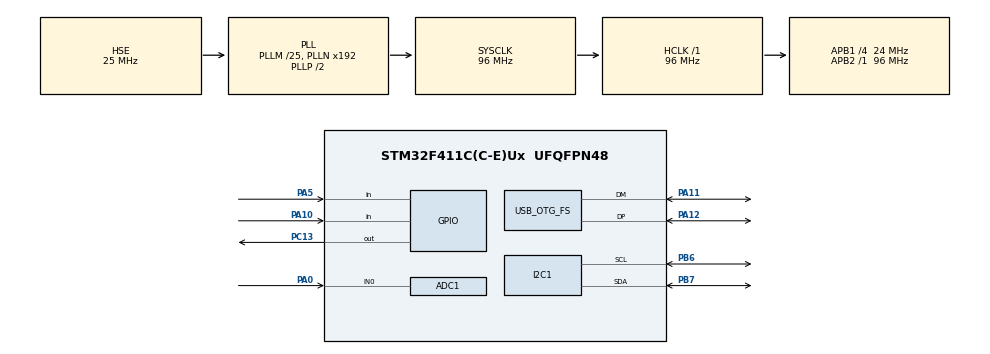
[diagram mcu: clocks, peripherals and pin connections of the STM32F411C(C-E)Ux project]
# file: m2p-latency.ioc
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ADC1.Channel-0\#ChannelRegularConversion=ADC_CHANNEL_0
ADC1.NbrOfConversionFlag=1
ADC1.Rank-0\#ChannelRegularConversion=1
ADC1.SamplingTime-0\#ChannelRegularConversion=ADC_SAMPLETIME_3CYCLES
ADC1.master=1
I2C1.I2C_Mode=I2C_Fast
Mcu.Family=STM32F4
Mcu.Name=STM32F411C(C-E)Ux
Mcu.Package=UFQFPN48
NVIC.OTG_FS_IRQn=true\:0\:0\:false\:false\:true\:true\:true\:true
NVIC.PriorityGroup=NVIC_PRIORITYGROUP_4
PA0-WKUP.Signal=ADCx_IN0
PA10.GPIO_PuPd=GPIO_PULLUP
PA10.Signal=GPIO_Input
PA11.Mode=Device_Only
PA11.Signal=USB_OTG_FS_DM
PA12.Mode=Device_Only
PA12.Signal=USB_OTG_FS_DP
PA13.Mode=Serial_Wire
PA13.Signal=SYS_JTMS-SWDIO
PA14.Mode=Serial_Wire
PA14.Signal=SYS_JTCK-SWCLK
PA5.Signal=GPIO_Input
PB6.Mode=I2C
PB6.Signal=I2C1_SCL
PB7.Mode=I2C
PB7.Signal=I2C1_SDA
PC13-ANTI_TAMP.Signal=GPIO_Output
PH0\ -\ OSC_IN.Mode=HSE-External-Oscillator
PH0\ -\ OSC_IN.Signal=RCC_OSC_IN
PH1\ -\ OSC_OUT.Mode=HSE-External-Oscillator
PH1\ -\ OSC_OUT.Signal=RCC_OSC_OUT
ProjectManager.HeapSize=0x200
ProjectManager.StackSize=0x400
ProjectManager.TargetToolchain=Makefile
RCC.48MHZClocksFreq_Value=48000000
RCC.AHBFreq_Value=96000000
RCC.APB1CLKDivider=RCC_HCLK_DIV4
RCC.APB1Freq_Value=24000000
RCC.APB1TimFreq_Value=48000000
RCC.APB2Freq_Value=96000000
RCC.APB2TimFreq_Value=96000000
RCC.CortexFreq_Value=96000000
RCC.HCLKFreq_Value=96000000
RCC.HSE_VALUE=25000000
RCC.HSI_VALUE=16000000
RCC.LSE_VALUE=32768
RCC.PLLM=25
RCC.PLLSourceVirtual=RCC_PLLSOURCE_HSE
RCC.SYSCLKFreq_VALUE=96000000
RCC.SYSCLKSource=RCC_SYSCLKSOURCE_PLLCLK
RCC.VCOOutputFreq_Value=192000000
SH.ADCx_IN0.0=ADC1_IN0,IN0
TIM2.Prescaler=47
USB_DEVICE.CLASS_NAME_FS=HID
USB_DEVICE.HID_FS_BINTERVAL=0x1
USB_DEVICE.VirtualMode=Hid
USB_DEVICE.VirtualModeFS=Hid_FS
USB_OTG_FS.VirtualMode=Device_Only
VP_TIM2_VS_ClockSourceINT.Mode=Internal
VP_USB_DEVICE_VS_USB_DEVICE_HID_FS.Mode=HID_FS
board=custom

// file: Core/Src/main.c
/* USER CODE BEGIN Header */
/**
  ******************************************************************************
  * @file           : main.c
  * @brief          : Main program body
  ******************************************************************************
  * @attention
  *
  * Copyright (c) 2026 STMicroelectronics.
  * All rights reserved.
  *
  * This software is licensed under terms that can be found in the LICENSE file
  * in the root directory of this software component.
  * If no LICENSE file comes with this software, it is provided AS-IS.
  *
  ******************************************************************************
  */
/* USER CODE END Header */
#include "main.h"
#include "usb_device.h"

/* USER CODE BEGIN Includes */

#include "ssd1306.h"
#include "display.h"
#include "measure.h"
#include "usbd_hid.h"

/* USER CODE END Includes */

ADC_HandleTypeDef hadc1;

I2C_HandleTypeDef hi2c1;

TIM_HandleTypeDef htim2;

/* USER CODE BEGIN PV */

uint32_t latencies_us[NUM_CYCLES] = {};
uint16_t cycle_index = 0;
uint8_t hid_report[HID_REPORT_SIZE] = {0};

enum MouseMode {
  CLICK = 0,
  MOVE = 1
};

enum MouseMode selectedMode = CLICK;

extern USBD_HandleTypeDef hUsbDeviceFS;

/* USER CODE END PV */

void SystemClock_Config(void);
static void MX_GPIO_Init(void);
static void MX_ADC1_Init(void);
static void MX_I2C1_Init(void);
static void MX_TIM2_Init(void);
/* USER CODE BEGIN PFP */

uint32_t clickMouse();
void releaseMouse();
uint32_t moveMouse();
void moveBackMouse();
uint8_t HID_IsIdle (const USBD_HandleTypeDef *pdev);

/* USER CODE END PFP */

/* USER CODE BEGIN 0 */

uint32_t startMouseAction() {
  if (selectedMode == CLICK) {
    return clickMouse();
  }

  return moveMouse();
}

void stopMouseAction() {
  if (selectedMode == CLICK) {
    releaseMouse();
  } else {
    moveBackMouse();
  }
}

uint32_t moveMouse() {
  HAL_TIM_Base_Stop_IT(&htim2);
  __HAL_TIM_SET_COUNTER(&htim2, 0);
  HAL_TIM_Base_Start_IT(&htim2);

  hid_report[0] = 0;
  hid_report[1] = 127;
  hid_report[2] = 127;
  while (!HID_IsIdle(&hUsbDeviceFS)) {}
  const uint32_t timestamp = __HAL_TIM_GET_COUNTER(&htim2);
  USBD_HID_SendReport(&hUsbDeviceFS, hid_report, HID_REPORT_SIZE);

  return timestamp;
}

void moveBackMouse() {
  hid_report[0] = 0;
  hid_report[1] = -127;
  hid_report[2] = -127;
  while (!HID_IsIdle(&hUsbDeviceFS)) {}
  USBD_HID_SendReport(&hUsbDeviceFS, hid_report, HID_REPORT_SIZE);
}

uint32_t clickMouse() {
  HAL_TIM_Base_Stop_IT(&htim2);
  __HAL_TIM_SET_COUNTER(&htim2, 0);
  HAL_TIM_Base_Start_IT(&htim2);

  hid_report[0] = 1;
  while (!HID_IsIdle(&hUsbDeviceFS)) {}
  const uint32_t timestamp = __HAL_TIM_GET_COUNTER(&htim2);
  USBD_HID_SendReport(&hUsbDeviceFS, hid_report, HID_REPORT_SIZE);

  return timestamp;
}

void releaseMouse() {
  hid_report[0] = 0;
  while (!HID_IsIdle(&hUsbDeviceFS)) {}
  USBD_HID_SendReport(&hUsbDeviceFS, hid_report, HID_REPORT_SIZE);
}

uint8_t HID_IsIdle (const USBD_HandleTypeDef *pdev) {
  return ((USBD_HID_HandleTypeDef *)pdev->pClassData)->state == USBD_HID_IDLE;
}

/* USER CODE END 0 */

int main(void)
{

  /* MCU Configuration--------------------------------------------------------*/

  /* Reset of all peripherals, Initializes the Flash interface and the Systick. */
  HAL_Init();

  /* Configure the system clock */
  SystemClock_Config();

  /* Initialize all configured peripherals */
  MX_GPIO_Init();
  MX_ADC1_Init();
  MX_I2C1_Init();
  MX_TIM2_Init();
  MX_USB_DEVICE_Init();
  /* USER CODE BEGIN 2 */

  ssd1306_Init();
  drawSplashScreen();
  HAL_Delay(4000);

  uint32_t min_adc_val = readAveragedADC();
  uint32_t max_adc_val = min_adc_val;

  asm (".global _printf_float");

  /* USER CODE END 2 */

  /* Infinite loop */
  /* USER CODE BEGIN WHILE */
  while (1)
  {
    // wait for button press
    while (HAL_GPIO_ReadPin(BTN_CNT_GPIO_Port, BTN_CNT_Pin) == GPIO_PIN_SET) {
      if (HAL_GPIO_ReadPin(BTN_UP_GPIO_Port, BTN_UP_Pin) == GPIO_PIN_RESET) {
        selectedMode = MOVE;
      }

      if (HAL_GPIO_ReadPin(BTN_DN_GPIO_Port, BTN_DN_Pin) == GPIO_PIN_RESET) {
        selectedMode = CLICK;
      }

      const uint32_t adc_val = readAveragedADC();

      if (adc_val < min_adc_val) {
        min_adc_val = adc_val;
      } else if (adc_val > max_adc_val) {
        max_adc_val = adc_val;
      }

      drawStartupScreen(min_adc_val, max_adc_val, adc_val, selectedMode);

      HAL_Delay(10);
    }

    while (cycle_index < NUM_CYCLES) {
      measure();
      cycle_index++;
    }

    float mean_ms = 0.0f;
    float sd_ms = 0.0f;

    computeStatsMs(&mean_ms, &sd_ms);
    printAverage(mean_ms, sd_ms);
    HAL_Delay(10000);

    cycle_index = 0;

    /* USER CODE END WHILE */

  }
}

void SystemClock_Config(void)
{
  RCC_OscInitTypeDef RCC_OscInitStruct = {0};
  RCC_ClkInitTypeDef RCC_ClkInitStruct = {0};

  /** Configure the main internal regulator output voltage
  */
  __HAL_RCC_PWR_CLK_ENABLE();
  __HAL_PWR_VOLTAGESCALING_CONFIG(PWR_REGULATOR_VOLTAGE_SCALE1);

  /** Initializes the RCC Oscillators according to the specified parameters
  * in the RCC_OscInitTypeDef structure.
  */
  RCC_OscInitStruct.OscillatorType = RCC_OSCILLATORTYPE_HSE;
  RCC_OscInitStruct.HSEState = RCC_HSE_ON;
  RCC_OscInitStruct.PLL.PLLState = RCC_PLL_ON;
  RCC_OscInitStruct.PLL.PLLSource = RCC_PLLSOURCE_HSE;
  RCC_OscInitStruct.PLL.PLLM = 25;
  RCC_OscInitStruct.PLL.PLLN = 192;
  RCC_OscInitStruct.PLL.PLLP = RCC_PLLP_DIV2;
  RCC_OscInitStruct.PLL.PLLQ = 4;
  if (HAL_RCC_OscConfig(&RCC_OscInitStruct) != HAL_OK)
  {
    Error_Handler();
  }

  /** Initializes the CPU, AHB and APB buses clocks
  */
  RCC_ClkInitStruct.ClockType = RCC_CLOCKTYPE_HCLK|RCC_CLOCKTYPE_SYSCLK
                              |RCC_CLOCKTYPE_PCLK1|RCC_CLOCKTYPE_PCLK2;
  RCC_ClkInitStruct.SYSCLKSource = RCC_SYSCLKSOURCE_PLLCLK;
  RCC_ClkInitStruct.AHBCLKDivider = RCC_SYSCLK_DIV1;
  RCC_ClkInitStruct.APB1CLKDivider = RCC_HCLK_DIV4;
  RCC_ClkInitStruct.APB2CLKDivider = RCC_HCLK_DIV1;

  if (HAL_RCC_ClockConfig(&RCC_ClkInitStruct, FLASH_LATENCY_3) != HAL_OK)
  {
    Error_Handler();
  }
}

static void MX_ADC1_Init(void)
{

  ADC_ChannelConfTypeDef sConfig = {0};

  /** Configure the global features of the ADC (Clock, Resolution, Data Alignment and number of conversion)
  */
  hadc1.Instance = ADC1;
  hadc1.Init.ClockPrescaler = ADC_CLOCK_SYNC_PCLK_DIV4;
  hadc1.Init.Resolution = ADC_RESOLUTION_12B;
  hadc1.Init.ScanConvMode = DISABLE;
  hadc1.Init.ContinuousConvMode = DISABLE;
  hadc1.Init.DiscontinuousConvMode = DISABLE;
  hadc1.Init.ExternalTrigConvEdge = ADC_EXTERNALTRIGCONVEDGE_NONE;
  hadc1.Init.ExternalTrigConv = ADC_SOFTWARE_START;
  hadc1.Init.DataAlign = ADC_DATAALIGN_RIGHT;
  hadc1.Init.NbrOfConversion = 1;
  hadc1.Init.DMAContinuousRequests = DISABLE;
  hadc1.Init.EOCSelection = ADC_EOC_SINGLE_CONV;
  if (HAL_ADC_Init(&hadc1) != HAL_OK)
  {
    Error_Handler();
  }

  /** Configure for the selected ADC regular channel its corresponding rank in the sequencer and its sample time.
  */
  sConfig.Channel = ADC_CHANNEL_0;
  sConfig.Rank = 1;
  sConfig.SamplingTime = ADC_SAMPLETIME_3CYCLES;
  if (HAL_ADC_ConfigChannel(&hadc1, &sConfig) != HAL_OK)
  {
    Error_Handler();
  }

}

static void MX_I2C1_Init(void)
{

  hi2c1.Instance = I2C1;
  hi2c1.Init.ClockSpeed = 400000;
  hi2c1.Init.DutyCycle = I2C_DUTYCYCLE_2;
  hi2c1.Init.OwnAddress1 = 0;
  hi2c1.Init.AddressingMode = I2C_ADDRESSINGMODE_7BIT;
  hi2c1.Init.DualAddressMode = I2C_DUALADDRESS_DISABLE;
  hi2c1.Init.OwnAddress2 = 0;
  hi2c1.Init.GeneralCallMode = I2C_GENERALCALL_DISABLE;
  hi2c1.Init.NoStretchMode = I2C_NOSTRETCH_DISABLE;
  if (HAL_I2C_Init(&hi2c1) != HAL_OK)
  {
    Error_Handler();
  }

}

static void MX_TIM2_Init(void)
{

  TIM_ClockConfigTypeDef sClockSourceConfig = {0};
  TIM_MasterConfigTypeDef sMasterConfig = {0};

  htim2.Instance = TIM2;
  htim2.Init.Prescaler = 47;
  htim2.Init.CounterMode = TIM_COUNTERMODE_UP;
  htim2.Init.Period = 4294967295;
  htim2.Init.ClockDivision = TIM_CLOCKDIVISION_DIV1;
  htim2.Init.AutoReloadPreload = TIM_AUTORELOAD_PRELOAD_DISABLE;
  if (HAL_TIM_Base_Init(&htim2) != HAL_OK)
  {
    Error_Handler();
  }
  sClockSourceConfig.ClockSource = TIM_CLOCKSOURCE_INTERNAL;
  if (HAL_TIM_ConfigClockSource(&htim2, &sClockSourceConfig) != HAL_OK)
  {
    Error_Handler();
  }
  sMasterConfig.MasterOutputTrigger = TIM_TRGO_RESET;
  sMasterConfig.MasterSlaveMode = TIM_MASTERSLAVEMODE_DISABLE;
  if (HAL_TIMEx_MasterConfigSynchronization(&htim2, &sMasterConfig) != HAL_OK)
  {
    Error_Handler();
  }

}

static void MX_GPIO_Init(void)
{
  GPIO_InitTypeDef GPIO_InitStruct = {0};

  /* GPIO Ports Clock Enable */
  __HAL_RCC_GPIOC_CLK_ENABLE();
  __HAL_RCC_GPIOH_CLK_ENABLE();
  __HAL_RCC_GPIOA_CLK_ENABLE();
  __HAL_RCC_GPIOB_CLK_ENABLE();

  /*Configure GPIO pin Output Level */
  HAL_GPIO_WritePin(GPIOC, GPIO_PIN_13, GPIO_PIN_RESET);

  /*Configure GPIO pin : PC13 */
  GPIO_InitStruct.Pin = GPIO_PIN_13;
  GPIO_InitStruct.Mode = GPIO_MODE_OUTPUT_PP;
  GPIO_InitStruct.Pull = GPIO_NOPULL;
  GPIO_InitStruct.Speed = GPIO_SPEED_FREQ_LOW;
  HAL_GPIO_Init(GPIOC, &GPIO_InitStruct);

  /*Configure GPIO pins : BTN_UP_Pin BTN_DN_Pin BTN_CNT_Pin */
  GPIO_InitStruct.Pin = BTN_UP_Pin|BTN_DN_Pin|BTN_CNT_Pin;
  GPIO_InitStruct.Mode = GPIO_MODE_INPUT;
  GPIO_InitStruct.Pull = GPIO_PULLUP;
  HAL_GPIO_Init(GPIOA, &GPIO_InitStruct);

}

void Error_Handler(void)
{
  __disable_irq();
  while (1)
  {
  }
}
